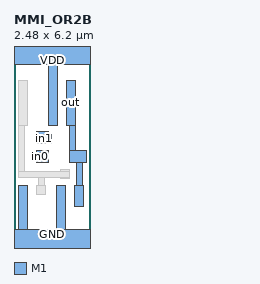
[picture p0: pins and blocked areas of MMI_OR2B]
MACRO MMI_OR2B
	CLASS CORE ;
	FOREIGN MMI_OR2B 0 0 ;
	SIZE 2.48 BY 6.2 ;
	SYMMETRY X Y ;
	SITE CORE1 ;
	PIN out
		DIRECTION output ;
		USE SIGNAL ;
		PORT
			LAYER M1 ;
			RECT 1.715 3.81 1.995 5.28 ;
			LAYER M1 ;
			RECT 1.8 2.98 1.995 3.81 ;
			LAYER M1 ;
			RECT 1.8 2.6 2.36 2.98 ;
			LAYER M1 ;
			RECT 2.03 1.85 2.22 2.6 ;
			LAYER M1 ;
			RECT 1.99 1.15 2.27 1.85 ;
		END
		AntennaDiffArea 0.91245 ;
	END out
	PIN in1
		DIRECTION input ;
		USE SIGNAL ;
		PORT
			LAYER M1 ;
			RECT 0.74 3.51 1.12 3.6 ;
			LAYER M1 ;
			RECT 0.74 3.23 1.225 3.51 ;
			LAYER M1 ;
			RECT 0.74 3.22 1.12 3.23 ;
		END
		AntennaGateArea 0.28875 ;
	END in1
	PIN GND
		DIRECTION inout ;
		USE GROUND ;
		PORT
			LAYER M1 ;
			RECT 0.16 0.42 0.44 1.85 ;
			LAYER M1 ;
			RECT 1.4 0.42 1.68 1.85 ;
			LAYER M1 ;
			RECT 0 -0.42 2.48 0.42 ;
		END
	END GND
	PIN VDD
		DIRECTION inout ;
		USE POWER ;
		PORT
			LAYER M1 ;
			RECT 0 5.78 2.48 6.62 ;
			LAYER M1 ;
			RECT 1.125 3.81 1.405 5.78 ;
		END
	END VDD
	PIN in0
		DIRECTION input ;
		USE SIGNAL ;
		PORT
			LAYER M1 ;
			RECT 0.74 2.93 1.12 2.98 ;
			LAYER M1 ;
			RECT 0.555 2.65 1.12 2.93 ;
			LAYER M1 ;
			RECT 0.74 2.6 1.12 2.65 ;
		END
		AntennaGateArea 0.28875 ;
	END in0
	OBS
		LAYER M1 ;
		RECT 0.16 3.81 0.44 5.28 ;
		LAYER M1 ;
		RECT 0.16 2.31 0.355 3.81 ;
		LAYER M1 ;
		RECT 1.52 2.31 1.8 2.35 ;
		LAYER M1 ;
		RECT 0.16 2.115 1.8 2.31 ;
		LAYER M1 ;
		RECT 0.795 1.85 0.985 2.115 ;
		LAYER M1 ;
		RECT 1.52 2.07 1.8 2.115 ;
		LAYER M1 ;
		RECT 0.75 1.535 1.03 1.85 ;
	END
END MMI_OR2B
